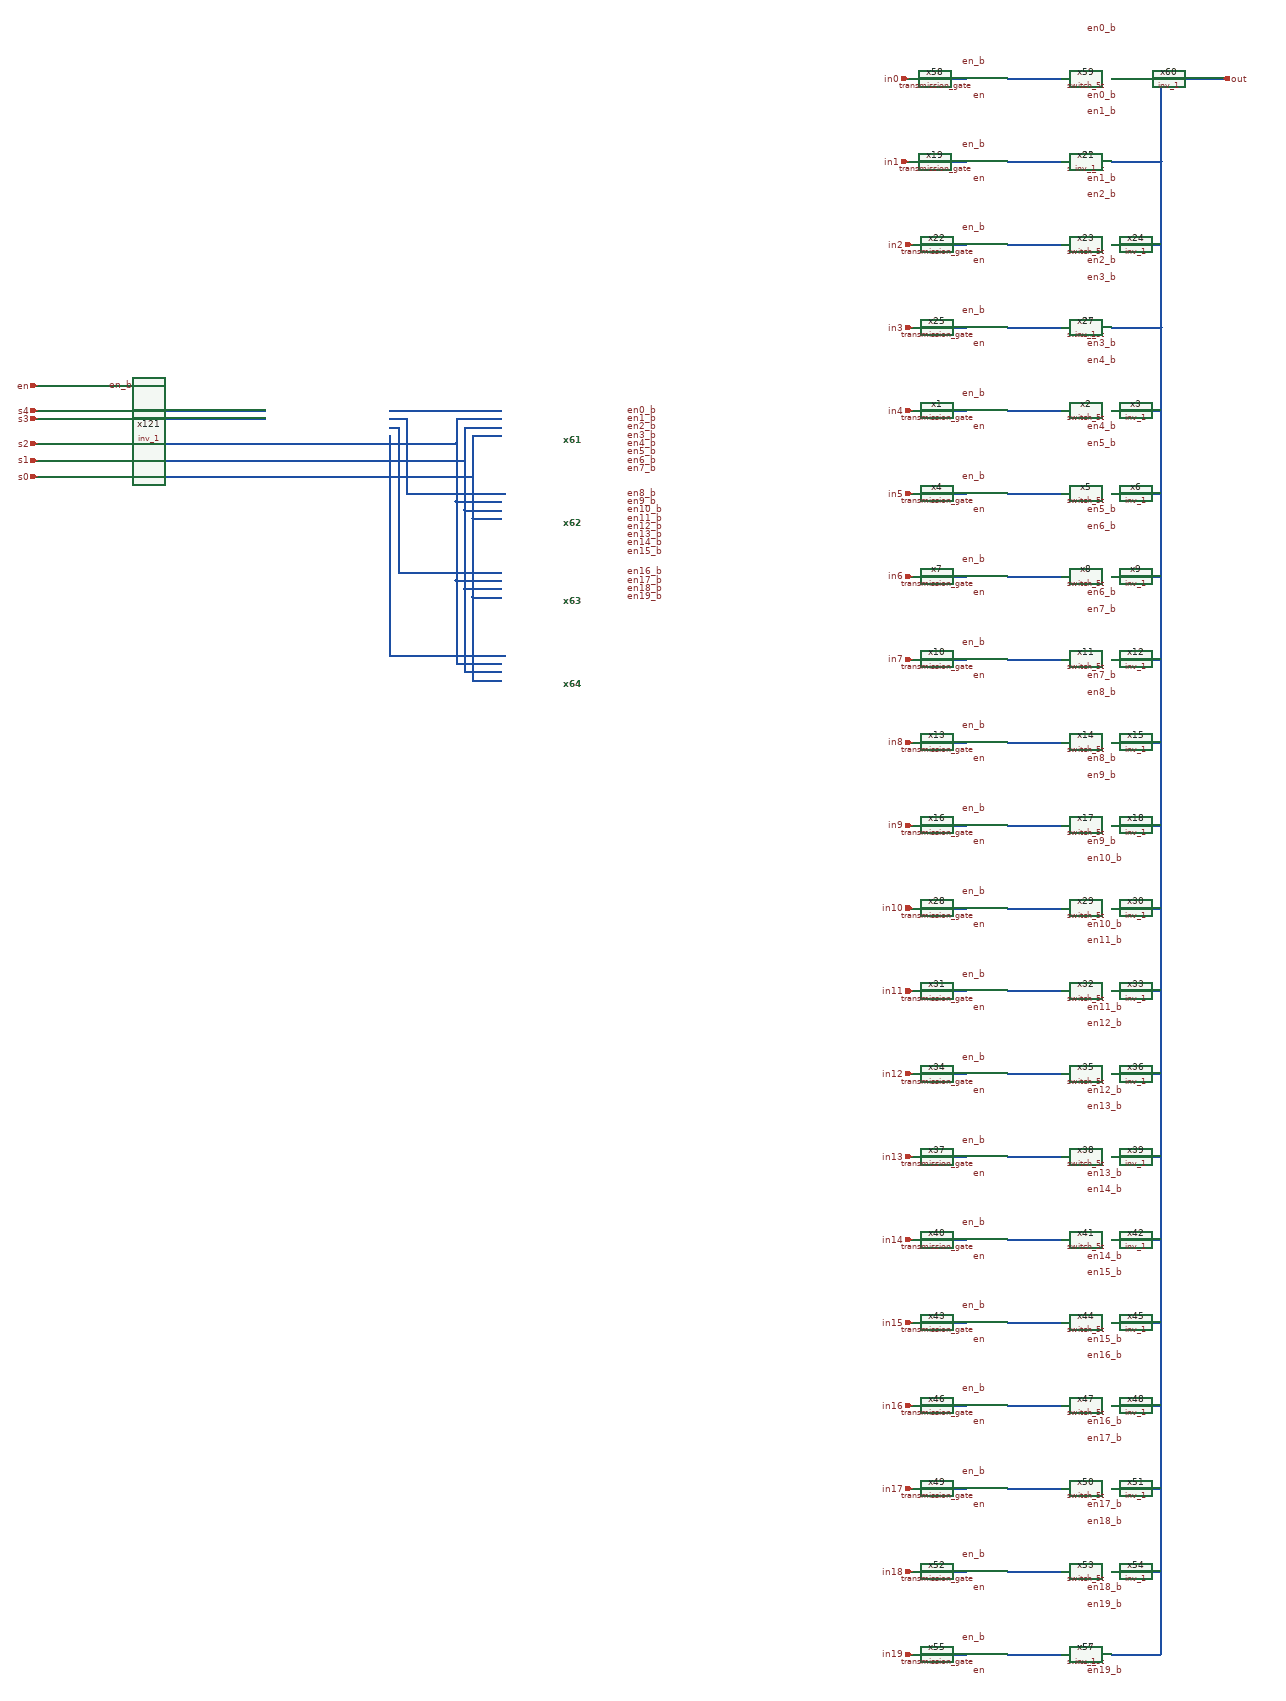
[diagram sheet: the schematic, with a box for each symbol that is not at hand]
v {xschem version=3.0.0 file_version=1.2 }
G {}
K {}
V {}
S {}
E {}
N -2080 760 -2060 760 { lab=en}
N -1980 760 -1960 760 { lab=en_b}
N 210 2020 340 2020 { lab=#net1}
N 60 2020 110 2020 { lab=in10}
N 210 2220 340 2220 { lab=#net2}
N 60 2220 110 2220 { lab=in11}
N 460 2220 580 2220 { lab=out}
N 210 2420 340 2420 { lab=#net3}
N 60 2420 110 2420 { lab=in12}
N 460 2420 580 2420 { lab=out}
N 460 2020 580 2020 { lab=out}
N 210 2620 340 2620 { lab=#net4}
N 60 2620 110 2620 { lab=in13}
N 210 2820 340 2820 { lab=#net5}
N 60 2820 110 2820 { lab=in14}
N 460 2820 580 2820 { lab=out}
N 210 3020 340 3020 { lab=#net6}
N 60 3020 110 3020 { lab=in15}
N 460 3020 580 3020 { lab=out}
N 460 2620 580 2620 { lab=out}
N 210 3220 340 3220 { lab=#net7}
N 60 3220 110 3220 { lab=in16}
N 460 3220 580 3220 { lab=out}
N 210 3420 340 3420 { lab=#net8}
N 60 3420 110 3420 { lab=in17}
N 460 3420 580 3420 { lab=out}
N 210 3620 340 3620 { lab=#net9}
N 60 3620 110 3620 { lab=in18}
N 210 3820 340 3820 { lab=#net10}
N 60 3820 110 3820 { lab=in19}
N 460 3820 580 3820 { lab=out}
N 460 3620 580 3620 { lab=out}
N 210 820 340 820 { lab=#net11}
N 60 820 110 820 { lab=in4}
N 460 820 580 820 { lab=out}
N 210 1020 340 1020 { lab=#net12}
N 60 1020 110 1020 { lab=in5}
N 460 1020 580 1020 { lab=out}
N 210 1220 340 1220 { lab=#net13}
N 60 1220 110 1220 { lab=in6}
N 460 1220 580 1220 { lab=out}
N 210 1420 340 1420 { lab=#net14}
N 60 1420 110 1420 { lab=in7}
N 460 1420 580 1420 { lab=out}
N 210 1620 340 1620 { lab=#net15}
N 60 1620 110 1620 { lab=in8}
N 210 1820 340 1820 { lab=#net16}
N 60 1820 110 1820 { lab=in9}
N 460 1820 580 1820 { lab=out}
N 460 1620 580 1620 { lab=out}
N 210 220 340 220 { lab=#net17}
N 60 220 110 220 { lab=in1}
N 460 220 580 220 { lab=out}
N 210 420 340 420 { lab=#net18}
N 60 420 110 420 { lab=in2}
N 460 420 580 420 { lab=out}
N 210 620 340 620 { lab=#net19}
N 60 620 110 620 { lab=in3}
N 460 620 580 620 { lab=out}
N 580 220 580 620 { lab=out}
N 580 20 680 20 { lab=out}
N 210 20 340 20 { lab=#net20}
N 60 20 110 20 { lab=in0}
N 460 20 580 20 { lab=out}
N 580 20 580 220 { lab=out}
N 580 620 580 3820 { lab=out}
N -1800 840 -1760 840 { lab=s3}
N -1800 820 -1760 820 { lab=s4}
N -1800 940 -1760 940 { lab=s1}
N -1800 900 -1760 900 { lab=s2}
N -1800 980 -1760 980 { lab=s0}
N -1760 820 -1580 820 { lab=s4}
N -1280 820 -1010 820 { lab=#net21}
N -1280 840 -1240 840 { lab=#net22}
N -1240 840 -1240 1020 { lab=#net22}
N -1240 1020 -1000 1020 { lab=#net22}
N -1280 860 -1260 860 { lab=#net23}
N -1260 860 -1260 1210 { lab=#net23}
N -1260 1210 -1010 1210 { lab=#net23}
N -1280 880 -1280 1410 { lab=#net24}
N -1280 1410 -1000 1410 { lab=#net24}
N -1760 900 -1120 900 { lab=s2}
N -1120 840 -1120 900 { lab=s2}
N -1120 840 -1010 840 { lab=s2}
N -1120 900 -1120 1040 { lab=s2}
N -1120 1040 -1010 1040 { lab=s2}
N -1120 1040 -1120 1230 { lab=s2}
N -1120 1230 -1010 1230 { lab=s2}
N -1120 1230 -1120 1430 { lab=s2}
N -1120 1430 -1010 1430 { lab=s2}
N -1760 940 -1100 940 { lab=s1}
N -1100 860 -1100 940 { lab=s1}
N -1100 860 -1010 860 { lab=s1}
N -1100 940 -1100 1060 { lab=s1}
N -1100 1060 -1010 1060 { lab=s1}
N -1100 1060 -1100 1250 { lab=s1}
N -1100 1250 -1010 1250 { lab=s1}
N -1100 1250 -1100 1450 { lab=s1}
N -1100 1450 -1010 1450 { lab=s1}
N -1760 980 -1080 980 { lab=s0}
N -1080 880 -1080 980 { lab=s0}
N -1080 880 -1010 880 { lab=s0}
N -1080 980 -1080 1080 { lab=s0}
N -1080 1080 -1010 1080 { lab=s0}
N -1080 1080 -1080 1270 { lab=s0}
N -1080 1270 -1010 1270 { lab=s0}
N -1080 1270 -1080 1470 { lab=s0}
N -1080 1470 -1010 1470 { lab=s0}
N -1760 840 -1580 840 { lab=s3}
N -2140 840 -1800 840 { lab=s3}
N -2140 820 -1800 820 { lab=s4}
N -2140 940 -1860 940 { lab=s1}
N -1860 940 -1800 940 { lab=s1}
N -2140 980 -1900 980 { lab=s0}
N -1900 980 -1800 980 { lab=s0}
N -2140 760 -2080 760 { lab=en}
N 680 20 740 20 { lab=out}
N -40 20 60 20 { lab=in0}
N -40 220 60 220 { lab=in1}
N -30 420 60 420 { lab=in2}
N -30 620 60 620 { lab=in3}
N -30 820 60 820 { lab=in4}
N -30 1020 60 1020 { lab=in5}
N -30 1220 60 1220 { lab=in6}
N -30 1420 60 1420 { lab=in7}
N -30 1620 60 1620 { lab=in8}
N -30 1820 60 1820 { lab=in9}
N -30 2020 60 2020 { lab=in10}
N -30 2220 60 2220 { lab=in11}
N -30 2420 60 2420 { lab=in12}
N -30 2620 60 2620 { lab=in13}
N -30 2820 60 2820 { lab=in14}
N -30 3020 60 3020 { lab=in15}
N -30 3220 60 3220 { lab=in16}
N -30 3420 60 3420 { lab=in17}
N -30 3620 60 3620 { lab=in18}
N -30 3820 60 3820 { lab=in19}
N -2140 900 -1800 900 { lab=s2}
C {sky130_stdcells/inv_1.sym} -2020 760 0 0 {name=x121 VGND=VGND VNB=VNB VPB=VPB VPWR=VPWR prefix=sky130_fd_sc_hd__ }
C {devices/lab_pin.sym} -1960 760 2 0 {name=l202 sig_type=std_logic lab=en_b}
C {transmission_gate.sym} 130 2020 0 0 {name=x28 VDD=VDD VSS=VSS N=1 W_N=5.3 L_N=0.15 W_P=13.7 L_P=0.15}
C {switch_5t.sym} 330 1970 2 1 {name=x29 VDD=VDD VSS=VSS}
C {sky130_stdcells/inv_1.sym} 400 1940 1 0 {name=x30 VGND=VGND VNB=VNB VPB=VPB VPWR=VPWR prefix=sky130_fd_sc_hd__ }
C {devices/lab_pin.sym} 400 2060 2 0 {name=l46 sig_type=std_logic lab=en10_b
}
C {devices/lab_pin.sym} 400 1900 2 0 {name=l47 sig_type=std_logic lab=en10_b
}
C {devices/lab_pin.sym} 160 1980 0 0 {name=l48 sig_type=std_logic lab=en_b}
C {devices/lab_pin.sym} 160 2060 0 0 {name=l49 sig_type=std_logic lab=en
}
C {transmission_gate.sym} 130 2220 0 0 {name=x31 VDD=VDD VSS=VSS N=1 W_N=5.3 L_N=0.15 W_P=13.7 L_P=0.15}
C {switch_5t.sym} 330 2170 2 1 {name=x32 VDD=VDD VSS=VSS}
C {sky130_stdcells/inv_1.sym} 400 2140 1 0 {name=x33 VGND=VGND VNB=VNB VPB=VPB VPWR=VPWR prefix=sky130_fd_sc_hd__ }
C {devices/lab_pin.sym} 400 2260 2 0 {name=l51 sig_type=std_logic lab=en11_b
}
C {devices/lab_pin.sym} 400 2100 2 0 {name=l52 sig_type=std_logic lab=en11_b
}
C {devices/lab_pin.sym} 160 2180 0 0 {name=l53 sig_type=std_logic lab=en_b}
C {devices/lab_pin.sym} 160 2260 0 0 {name=l54 sig_type=std_logic lab=en
}
C {transmission_gate.sym} 130 2420 0 0 {name=x34 VDD=VDD VSS=VSS N=1 W_N=5.3 L_N=0.15 W_P=13.7 L_P=0.15}
C {switch_5t.sym} 330 2370 2 1 {name=x35 VDD=VDD VSS=VSS}
C {sky130_stdcells/inv_1.sym} 400 2340 1 0 {name=x36 VGND=VGND VNB=VNB VPB=VPB VPWR=VPWR prefix=sky130_fd_sc_hd__ }
C {devices/lab_pin.sym} 400 2460 2 0 {name=l56 sig_type=std_logic lab=en12_b
}
C {devices/lab_pin.sym} 400 2300 2 0 {name=l57 sig_type=std_logic lab=en12_b
}
C {devices/lab_pin.sym} 160 2380 0 0 {name=l58 sig_type=std_logic lab=en_b}
C {devices/lab_pin.sym} 160 2460 0 0 {name=l59 sig_type=std_logic lab=en
}
C {transmission_gate.sym} 130 2620 0 0 {name=x37 VDD=VDD VSS=VSS N=1 W_N=5.3 L_N=0.15 W_P=13.7 L_P=0.15}
C {switch_5t.sym} 330 2570 2 1 {name=x38 VDD=VDD VSS=VSS}
C {sky130_stdcells/inv_1.sym} 400 2540 1 0 {name=x39 VGND=VGND VNB=VNB VPB=VPB VPWR=VPWR prefix=sky130_fd_sc_hd__ }
C {devices/lab_pin.sym} 400 2660 2 0 {name=l61 sig_type=std_logic lab=en13_b
}
C {devices/lab_pin.sym} 400 2500 2 0 {name=l62 sig_type=std_logic lab=en13_b
}
C {devices/lab_pin.sym} 160 2580 0 0 {name=l63 sig_type=std_logic lab=en_b}
C {devices/lab_pin.sym} 160 2660 0 0 {name=l64 sig_type=std_logic lab=en
}
C {transmission_gate.sym} 130 2820 0 0 {name=x40 VDD=VDD VSS=VSS N=1 W_N=5.3 L_N=0.15 W_P=13.7 L_P=0.15}
C {switch_5t.sym} 330 2770 2 1 {name=x41 VDD=VDD VSS=VSS}
C {sky130_stdcells/inv_1.sym} 400 2740 1 0 {name=x42 VGND=VGND VNB=VNB VPB=VPB VPWR=VPWR prefix=sky130_fd_sc_hd__ }
C {devices/lab_pin.sym} 400 2860 2 0 {name=l66 sig_type=std_logic lab=en14_b
}
C {devices/lab_pin.sym} 400 2700 2 0 {name=l67 sig_type=std_logic lab=en14_b
}
C {devices/lab_pin.sym} 160 2780 0 0 {name=l68 sig_type=std_logic lab=en_b}
C {devices/lab_pin.sym} 160 2860 0 0 {name=l69 sig_type=std_logic lab=en
}
C {transmission_gate.sym} 130 3020 0 0 {name=x43 VDD=VDD VSS=VSS N=1 W_N=5.3 L_N=0.15 W_P=13.7 L_P=0.15}
C {switch_5t.sym} 330 2970 2 1 {name=x44 VDD=VDD VSS=VSS}
C {sky130_stdcells/inv_1.sym} 400 2940 1 0 {name=x45 VGND=VGND VNB=VNB VPB=VPB VPWR=VPWR prefix=sky130_fd_sc_hd__ }
C {devices/lab_pin.sym} 400 3060 2 0 {name=l71 sig_type=std_logic lab=en15_b
}
C {devices/lab_pin.sym} 400 2900 2 0 {name=l72 sig_type=std_logic lab=en15_b
}
C {devices/lab_pin.sym} 160 2980 0 0 {name=l73 sig_type=std_logic lab=en_b}
C {devices/lab_pin.sym} 160 3060 0 0 {name=l74 sig_type=std_logic lab=en
}
C {transmission_gate.sym} 130 3220 0 0 {name=x46 VDD=VDD VSS=VSS N=1 W_N=5.3 L_N=0.15 W_P=13.7 L_P=0.15}
C {switch_5t.sym} 330 3170 2 1 {name=x47 VDD=VDD VSS=VSS}
C {sky130_stdcells/inv_1.sym} 400 3140 1 0 {name=x48 VGND=VGND VNB=VNB VPB=VPB VPWR=VPWR prefix=sky130_fd_sc_hd__ }
C {devices/lab_pin.sym} 400 3260 2 0 {name=l76 sig_type=std_logic lab=en16_b
}
C {devices/lab_pin.sym} 400 3100 2 0 {name=l77 sig_type=std_logic lab=en16_b
}
C {devices/lab_pin.sym} 160 3180 0 0 {name=l78 sig_type=std_logic lab=en_b}
C {devices/lab_pin.sym} 160 3260 0 0 {name=l79 sig_type=std_logic lab=en
}
C {transmission_gate.sym} 130 3420 0 0 {name=x49 VDD=VDD VSS=VSS N=1 W_N=5.3 L_N=0.15 W_P=13.7 L_P=0.15}
C {switch_5t.sym} 330 3370 2 1 {name=x50 VDD=VDD VSS=VSS}
C {sky130_stdcells/inv_1.sym} 400 3340 1 0 {name=x51 VGND=VGND VNB=VNB VPB=VPB VPWR=VPWR prefix=sky130_fd_sc_hd__ }
C {devices/lab_pin.sym} 400 3460 2 0 {name=l81 sig_type=std_logic lab=en17_b
}
C {devices/lab_pin.sym} 400 3300 2 0 {name=l82 sig_type=std_logic lab=en17_b
}
C {devices/lab_pin.sym} 160 3380 0 0 {name=l83 sig_type=std_logic lab=en_b}
C {devices/lab_pin.sym} 160 3460 0 0 {name=l84 sig_type=std_logic lab=en
}
C {transmission_gate.sym} 130 3620 0 0 {name=x52 VDD=VDD VSS=VSS N=1 W_N=5.3 L_N=0.15 W_P=13.7 L_P=0.15}
C {switch_5t.sym} 330 3570 2 1 {name=x53 VDD=VDD VSS=VSS}
C {sky130_stdcells/inv_1.sym} 400 3540 1 0 {name=x54 VGND=VGND VNB=VNB VPB=VPB VPWR=VPWR prefix=sky130_fd_sc_hd__ }
C {devices/lab_pin.sym} 400 3660 2 0 {name=l86 sig_type=std_logic lab=en18_b
}
C {devices/lab_pin.sym} 400 3500 2 0 {name=l87 sig_type=std_logic lab=en18_b
}
C {devices/lab_pin.sym} 160 3580 0 0 {name=l88 sig_type=std_logic lab=en_b}
C {devices/lab_pin.sym} 160 3660 0 0 {name=l89 sig_type=std_logic lab=en
}
C {transmission_gate.sym} 130 3820 0 0 {name=x55 VDD=VDD VSS=VSS N=1 W_N=5.3 L_N=0.15 W_P=13.7 L_P=0.15}
C {switch_5t.sym} 330 3770 2 1 {name=x56 VDD=VDD VSS=VSS}
C {sky130_stdcells/inv_1.sym} 400 3740 1 0 {name=x57 VGND=VGND VNB=VNB VPB=VPB VPWR=VPWR prefix=sky130_fd_sc_hd__ }
C {devices/lab_pin.sym} 400 3860 2 0 {name=l91 sig_type=std_logic lab=en19_b
}
C {devices/lab_pin.sym} 400 3700 2 0 {name=l92 sig_type=std_logic lab=en19_b
}
C {devices/lab_pin.sym} 160 3780 0 0 {name=l93 sig_type=std_logic lab=en_b}
C {devices/lab_pin.sym} 160 3860 0 0 {name=l94 sig_type=std_logic lab=en
}
C {transmission_gate.sym} 130 820 0 0 {name=x1 VDD=VDD VSS=VSS N=1 W_N=5.3 L_N=0.15 W_P=13.7 L_P=0.15}
C {switch_5t.sym} 330 770 2 1 {name=x2 VDD=VDD VSS=VSS}
C {sky130_stdcells/inv_1.sym} 400 740 1 0 {name=x3 VGND=VGND VNB=VNB VPB=VPB VPWR=VPWR prefix=sky130_fd_sc_hd__ }
C {devices/lab_pin.sym} 400 860 2 0 {name=l1 sig_type=std_logic lab=en4_b
}
C {devices/lab_pin.sym} 400 700 2 0 {name=l2 sig_type=std_logic lab=en4_b
}
C {devices/lab_pin.sym} 160 780 0 0 {name=l3 sig_type=std_logic lab=en_b}
C {devices/lab_pin.sym} 160 860 0 0 {name=l4 sig_type=std_logic lab=en
}
C {transmission_gate.sym} 130 1020 0 0 {name=x4 VDD=VDD VSS=VSS N=1 W_N=5.3 L_N=0.15 W_P=13.7 L_P=0.15}
C {switch_5t.sym} 330 970 2 1 {name=x5 VDD=VDD VSS=VSS}
C {sky130_stdcells/inv_1.sym} 400 940 1 0 {name=x6 VGND=VGND VNB=VNB VPB=VPB VPWR=VPWR prefix=sky130_fd_sc_hd__ }
C {devices/lab_pin.sym} 400 1060 2 0 {name=l6 sig_type=std_logic lab=en5_b
}
C {devices/lab_pin.sym} 400 900 2 0 {name=l7 sig_type=std_logic lab=en5_b
}
C {devices/lab_pin.sym} 160 980 0 0 {name=l8 sig_type=std_logic lab=en_b}
C {devices/lab_pin.sym} 160 1060 0 0 {name=l9 sig_type=std_logic lab=en
}
C {transmission_gate.sym} 130 1220 0 0 {name=x7 VDD=VDD VSS=VSS N=1 W_N=5.3 L_N=0.15 W_P=13.7 L_P=0.15}
C {switch_5t.sym} 330 1170 2 1 {name=x8 VDD=VDD VSS=VSS}
C {sky130_stdcells/inv_1.sym} 400 1140 1 0 {name=x9 VGND=VGND VNB=VNB VPB=VPB VPWR=VPWR prefix=sky130_fd_sc_hd__ }
C {devices/lab_pin.sym} 400 1260 2 0 {name=l11 sig_type=std_logic lab=en6_b
}
C {devices/lab_pin.sym} 400 1100 2 0 {name=l12 sig_type=std_logic lab=en6_b
}
C {devices/lab_pin.sym} 160 1180 0 0 {name=l13 sig_type=std_logic lab=en_b}
C {devices/lab_pin.sym} 160 1260 0 0 {name=l14 sig_type=std_logic lab=en
}
C {transmission_gate.sym} 130 1420 0 0 {name=x10 VDD=VDD VSS=VSS N=1 W_N=5.3 L_N=0.15 W_P=13.7 L_P=0.15}
C {switch_5t.sym} 330 1370 2 1 {name=x11 VDD=VDD VSS=VSS}
C {sky130_stdcells/inv_1.sym} 400 1340 1 0 {name=x12 VGND=VGND VNB=VNB VPB=VPB VPWR=VPWR prefix=sky130_fd_sc_hd__ }
C {devices/lab_pin.sym} 400 1460 2 0 {name=l16 sig_type=std_logic lab=en7_b
}
C {devices/lab_pin.sym} 400 1300 2 0 {name=l17 sig_type=std_logic lab=en7_b
}
C {devices/lab_pin.sym} 160 1380 0 0 {name=l18 sig_type=std_logic lab=en_b}
C {devices/lab_pin.sym} 160 1460 0 0 {name=l19 sig_type=std_logic lab=en
}
C {transmission_gate.sym} 130 1620 0 0 {name=x13 VDD=VDD VSS=VSS N=1 W_N=5.3 L_N=0.15 W_P=13.7 L_P=0.15}
C {switch_5t.sym} 330 1570 2 1 {name=x14 VDD=VDD VSS=VSS}
C {sky130_stdcells/inv_1.sym} 400 1540 1 0 {name=x15 VGND=VGND VNB=VNB VPB=VPB VPWR=VPWR prefix=sky130_fd_sc_hd__ }
C {devices/lab_pin.sym} 400 1660 2 0 {name=l21 sig_type=std_logic lab=en8_b
}
C {devices/lab_pin.sym} 400 1500 2 0 {name=l22 sig_type=std_logic lab=en8_b
}
C {devices/lab_pin.sym} 160 1580 0 0 {name=l23 sig_type=std_logic lab=en_b}
C {devices/lab_pin.sym} 160 1660 0 0 {name=l24 sig_type=std_logic lab=en
}
C {transmission_gate.sym} 130 1820 0 0 {name=x16 VDD=VDD VSS=VSS N=1 W_N=5.3 L_N=0.15 W_P=13.7 L_P=0.15}
C {switch_5t.sym} 330 1770 2 1 {name=x17 VDD=VDD VSS=VSS}
C {sky130_stdcells/inv_1.sym} 400 1740 1 0 {name=x18 VGND=VGND VNB=VNB VPB=VPB VPWR=VPWR prefix=sky130_fd_sc_hd__ }
C {devices/lab_pin.sym} 400 1860 2 0 {name=l26 sig_type=std_logic lab=en9_b
}
C {devices/lab_pin.sym} 400 1700 2 0 {name=l27 sig_type=std_logic lab=en9_b
}
C {devices/lab_pin.sym} 160 1780 0 0 {name=l28 sig_type=std_logic lab=en_b}
C {devices/lab_pin.sym} 160 1860 0 0 {name=l29 sig_type=std_logic lab=en
}
C {transmission_gate.sym} 130 220 0 0 {name=x19 VDD=VDD VSS=VSS N=1 W_N=5.3 L_N=0.15 W_P=13.7 L_P=0.15}
C {switch_5t.sym} 330 170 2 1 {name=x20 VDD=VDD VSS=VSS}
C {sky130_stdcells/inv_1.sym} 400 140 1 0 {name=x21 VGND=VGND VNB=VNB VPB=VPB VPWR=VPWR prefix=sky130_fd_sc_hd__ }
C {devices/lab_pin.sym} 400 260 2 0 {name=l31 sig_type=std_logic lab=en1_b
}
C {devices/lab_pin.sym} 400 100 2 0 {name=l32 sig_type=std_logic lab=en1_b
}
C {devices/lab_pin.sym} 160 180 0 0 {name=l33 sig_type=std_logic lab=en_b}
C {devices/lab_pin.sym} 160 260 0 0 {name=l34 sig_type=std_logic lab=en
}
C {transmission_gate.sym} 130 420 0 0 {name=x22 VDD=VDD VSS=VSS N=1 W_N=5.3 L_N=0.15 W_P=13.7 L_P=0.15}
C {switch_5t.sym} 330 370 2 1 {name=x23 VDD=VDD VSS=VSS}
C {sky130_stdcells/inv_1.sym} 400 340 1 0 {name=x24 VGND=VGND VNB=VNB VPB=VPB VPWR=VPWR prefix=sky130_fd_sc_hd__ }
C {devices/lab_pin.sym} 400 460 2 0 {name=l36 sig_type=std_logic lab=en2_b
}
C {devices/lab_pin.sym} 400 300 2 0 {name=l37 sig_type=std_logic lab=en2_b
}
C {devices/lab_pin.sym} 160 380 0 0 {name=l38 sig_type=std_logic lab=en_b}
C {devices/lab_pin.sym} 160 460 0 0 {name=l39 sig_type=std_logic lab=en
}
C {transmission_gate.sym} 130 620 0 0 {name=x25 VDD=VDD VSS=VSS N=1 W_N=5.3 L_N=0.15 W_P=13.7 L_P=0.15}
C {switch_5t.sym} 330 570 2 1 {name=x26 VDD=VDD VSS=VSS}
C {sky130_stdcells/inv_1.sym} 400 540 1 0 {name=x27 VGND=VGND VNB=VNB VPB=VPB VPWR=VPWR prefix=sky130_fd_sc_hd__ }
C {devices/lab_pin.sym} 400 660 2 0 {name=l41 sig_type=std_logic lab=en3_b
}
C {devices/lab_pin.sym} 400 500 2 0 {name=l42 sig_type=std_logic lab=en3_b
}
C {devices/lab_pin.sym} 160 580 0 0 {name=l43 sig_type=std_logic lab=en_b}
C {devices/lab_pin.sym} 160 660 0 0 {name=l44 sig_type=std_logic lab=en
}
C {transmission_gate.sym} 130 20 0 0 {name=x58 VDD=VDD VSS=VSS N=1 W_N=5.3 L_N=0.15 W_P=13.7 L_P=0.15}
C {switch_5t.sym} 330 -30 2 1 {name=x59 VDD=VDD VSS=VSS}
C {sky130_stdcells/inv_1.sym} 400 -60 1 0 {name=x60 VGND=VGND VNB=VNB VPB=VPB VPWR=VPWR prefix=sky130_fd_sc_hd__ }
C {devices/lab_pin.sym} 400 60 2 0 {name=l96 sig_type=std_logic lab=en0_b
}
C {devices/lab_pin.sym} 400 -100 2 0 {name=l97 sig_type=std_logic lab=en0_b
}
C {devices/lab_pin.sym} 160 -20 0 0 {name=l98 sig_type=std_logic lab=en_b}
C {devices/lab_pin.sym} 160 60 0 0 {name=l99 sig_type=std_logic lab=en
}
C {2to4_decoder.sym} -1430 850 0 0 {}
C {devices/ipin.sym} -2130 820 0 0 {name=p22 lab=s4
}
C {devices/ipin.sym} -2130 840 0 0 {name=p23 lab=s3


}
C {devices/ipin.sym} -2130 900 0 0 {name=p24 lab=s2



}
C {devices/ipin.sym} -2130 940 0 0 {name=p25 lab=s1




}
C {devices/ipin.sym} -2130 980 0 0 {name=p26 lab=s0





}
C {devices/lab_pin.sym} -710 820 2 0 {name=l102 sig_type=std_logic lab=en0_b
}
C {devices/lab_pin.sym} -710 840 2 0 {name=l103 sig_type=std_logic lab=en1_b
}
C {devices/lab_pin.sym} -710 860 2 0 {name=l104 sig_type=std_logic lab=en2_b
}
C {devices/lab_pin.sym} -710 880 2 0 {name=l105 sig_type=std_logic lab=en3_b
}
C {devices/lab_pin.sym} -710 900 2 0 {name=l106 sig_type=std_logic lab=en4_b
}
C {devices/lab_pin.sym} -710 920 2 0 {name=l107 sig_type=std_logic lab=en5_b
}
C {devices/lab_pin.sym} -710 940 2 0 {name=l110 sig_type=std_logic lab=en6_b
}
C {devices/lab_pin.sym} -710 960 2 0 {name=l111 sig_type=std_logic lab=en7_b
}
C {devices/lab_pin.sym} -710 1020 2 0 {name=l112 sig_type=std_logic lab=en8_b
}
C {devices/lab_pin.sym} -710 1040 2 0 {name=l113 sig_type=std_logic lab=en9_b
}
C {devices/lab_pin.sym} -710 1060 2 0 {name=l117 sig_type=std_logic lab=en10_b
}
C {devices/lab_pin.sym} -710 1080 2 0 {name=l118 sig_type=std_logic lab=en11_b
}
C {devices/lab_pin.sym} -710 1100 2 0 {name=l119 sig_type=std_logic lab=en12_b
}
C {devices/lab_pin.sym} -710 1120 2 0 {name=l120 sig_type=std_logic lab=en13_b
}
C {devices/lab_pin.sym} -710 1140 2 0 {name=l121 sig_type=std_logic lab=en14_b
}
C {devices/lab_pin.sym} -710 1160 2 0 {name=l122 sig_type=std_logic lab=en15_b
}
C {devices/lab_pin.sym} -710 1210 2 0 {name=l123 sig_type=std_logic lab=en16_b
}
C {devices/lab_pin.sym} -710 1230 2 0 {name=l124 sig_type=std_logic lab=en17_b
}
C {devices/lab_pin.sym} -710 1250 2 0 {name=l125 sig_type=std_logic lab=en18_b
}
C {devices/lab_pin.sym} -710 1270 2 0 {name=l126 sig_type=std_logic lab=en19_b
}
C {devices/ipin.sym} -20 1020 0 0 {name=p32 lab=in5





}
C {devices/ipin.sym} -20 1220 0 0 {name=p33 lab=in6






}
C {devices/ipin.sym} -20 1420 0 0 {name=p34 lab=in7







}
C {devices/ipin.sym} -20 1620 0 0 {name=p35 lab=in8








}
C {devices/ipin.sym} -20 1820 0 0 {name=p36 lab=in9









}
C {devices/ipin.sym} -20 2020 0 0 {name=p37 lab=in10










}
C {devices/ipin.sym} -20 2220 0 0 {name=p38 lab=in11










}
C {devices/ipin.sym} -20 2420 0 0 {name=p39 lab=in12










}
C {devices/ipin.sym} -20 2620 0 0 {name=p40 lab=in13










}
C {devices/ipin.sym} -20 2820 0 0 {name=p41 lab=in14










}
C {devices/ipin.sym} -20 3020 0 0 {name=p42 lab=in15










}
C {devices/ipin.sym} -20 3220 0 0 {name=p43 lab=in16











}
C {devices/ipin.sym} -20 3420 0 0 {name=p44 lab=in17













}
C {devices/ipin.sym} -20 3620 0 0 {name=p45 lab=in18














}
C {devices/ipin.sym} -20 3820 0 0 {name=p46 lab=in19















}
C {devices/ipin.sym} -2130 760 0 0 {name=p1 lab=en

}
C {devices/opin.sym} 730 20 0 0 {name=p21 lab=out}
C {devices/ipin.sym} -30 20 0 0 {name=p27 lab=in0
}
C {devices/ipin.sym} -30 220 0 0 {name=p28 lab=in1

}
C {devices/ipin.sym} -20 420 0 0 {name=p29 lab=in2


}
C {devices/ipin.sym} -20 620 0 0 {name=p30 lab=in3



}
C {devices/ipin.sym} -20 820 0 0 {name=p31 lab=in4




}
C {3to8_decoder.sym} -860 890 0 0 {name=x61}
C {3to8_decoder.sym} -860 1090 0 0 {name=x62}
C {3to8_decoder.sym} -860 1280 0 0 {name=x63}
C {3to8_decoder.sym} -860 1480 0 0 {name=x64}
